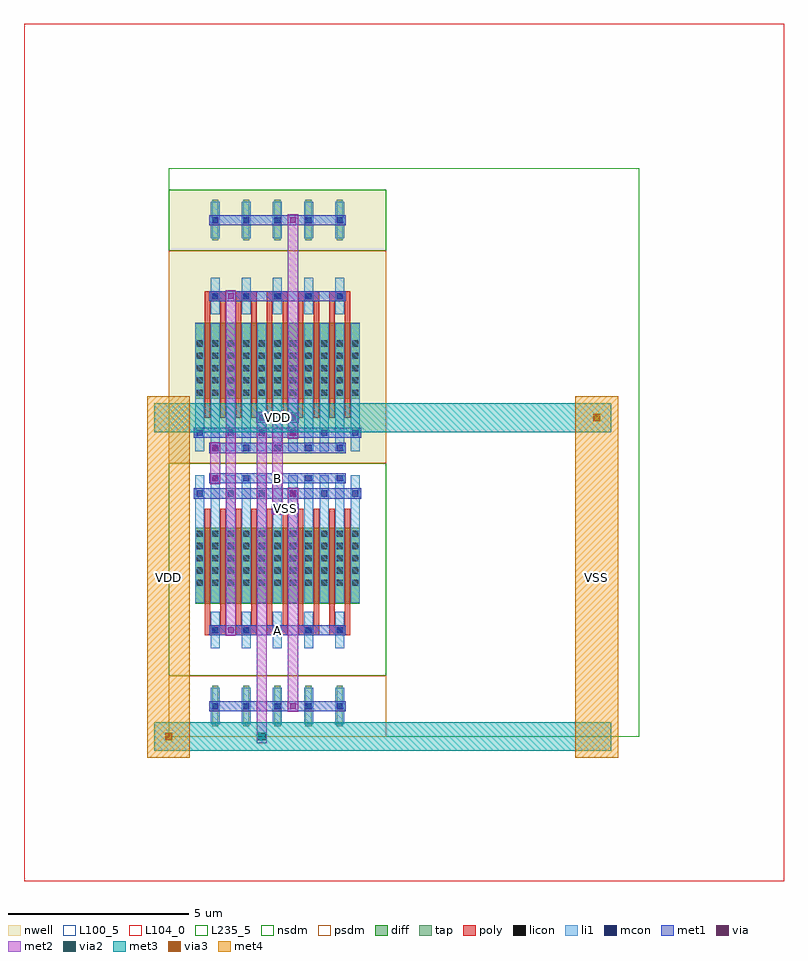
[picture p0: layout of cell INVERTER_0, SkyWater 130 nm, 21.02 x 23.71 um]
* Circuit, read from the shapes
.subckt INVERTER_0 A B VDD VSS
XM1 B A VSS VSS sky130_fd_pr__nfet_01v8 w=2.1 l=0.15 m=10
XM2 B A VDD VDD sky130_fd_pr__pfet_01v8 w=2.1 l=0.15 m=10
.ends

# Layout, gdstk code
import gdstk
lib = gdstk.Library(unit=1e-6, precision=1e-09)
def R(c, l, rs):  # rectangles x0, y0, x1, y1
    for r in rs: c.add(gdstk.rectangle(r[:2], r[2:], *l))
def A(c, l, x, y, w, h, nx, ny, dx, dy):  # array of equal rectangles
    R(c, l, [(x+i*dx, y+j*dy, x+i*dx+w, y+j*dy+h) for i in range(nx) for j in range(ny)])
def P(c, l, *ps):  # polygons
    for p in ps: c.add(gdstk.Polygon(p, *l))
nwell = (64, 20)
diff = (65, 20)
tap = (65, 44)
poly = (66, 20)
licon = (66, 44)
li1 = (67, 20)
mcon = (67, 44)
met1 = (68, 20)
via = (68, 44)
met2 = (69, 20)
via2 = (69, 44)
met3 = (70, 20)
via3 = (70, 44)
met4 = (71, 20)
nsdm = (93, 44)
psdm = (94, 20)
L100_5 = (100, 5)
L104_0 = (104, 0)
L235_5 = (235, 5)

nmos_s_97854001_x5_y1_16 = lib.new_cell('NMOS_S_97854001_X5_Y1_1676573813_1676573813')
R(nmos_s_97854001_x5_y1_16, diff, [(0.735,1.785,5.285,3.885)])
A(nmos_s_97854001_x5_y1_16, tap, 1.205, 6.16, 0.17, 1.12, 5, 1, 0.86, 0)
A(nmos_s_97854001_x5_y1_16, poly, 1, 1.26, 0.15, 3.36, 10, 1, 0.43, 0)
A(nmos_s_97854001_x5_y1_16, poly, 1, 4.485, 0.58, 0.27, 5, 1, 0.86, 0)
A(nmos_s_97854001_x5_y1_16, licon, 0.775, 1.865, 0.17, 0.17, 3, 5, 0.43, 0.34)
A(nmos_s_97854001_x5_y1_16, licon, 1.635, 1.865, 0.17, 0.17, 3, 5, 0.43, 0.34)
A(nmos_s_97854001_x5_y1_16, licon, 2.495, 1.865, 0.17, 0.17, 3, 5, 0.43, 0.34)
A(nmos_s_97854001_x5_y1_16, licon, 3.355, 1.865, 0.17, 0.17, 3, 5, 0.43, 0.34)
A(nmos_s_97854001_x5_y1_16, licon, 4.215, 1.865, 0.17, 0.17, 3, 5, 0.43, 0.34)
A(nmos_s_97854001_x5_y1_16, licon, 1.205, 4.535, 0.17, 0.17, 5, 2, 0.86, 2.1)
A(nmos_s_97854001_x5_y1_16, li1, 0.735, 0.335, 0.25, 3.53, 11, 1, 0.43, 0)
A(nmos_s_97854001_x5_y1_16, li1, 1.165, 4.115, 0.25, 1.01, 5, 2, 0.86, 2.1)
A(nmos_s_97854001_x5_y1_16, mcon, 1.205, 0.335, 0.17, 0.17, 5, 2, 0.86, 4.2)
A(nmos_s_97854001_x5_y1_16, mcon, 0.775, 0.755, 0.17, 0.17, 6, 1, 0.86, 0)
A(nmos_s_97854001_x5_y1_16, mcon, 1.205, 6.635, 0.17, 0.17, 5, 1, 0.86, 0)
R(nmos_s_97854001_x5_y1_16, met1, [(1.12,0.28,4.9,0.56), (0.69,0.7,5.33,0.98), (1.12,4.48,4.9,4.76), (1.12,6.58,4.9,6.86)])
R(nmos_s_97854001_x5_y1_16, via, [(3.365,0.765,3.515,0.915), (3.365,6.645,3.515,6.795)])
R(nmos_s_97854001_x5_y1_16, met2, [(3.3,0.68,3.58,6.88)])
R(nmos_s_97854001_x5_y1_16, nsdm, [(0,0,6.02,5.88)])
R(nmos_s_97854001_x5_y1_16, psdm, [(0,5.88,6.02,7.56)])
R(nmos_s_97854001_x5_y1_16, L100_5, [(0,0,6.02,7.56)])

pmos_s_86637345_x5_y1_16 = lib.new_cell('PMOS_S_86637345_X5_Y1_1676573814_1676573813')
R(pmos_s_86637345_x5_y1_16, nwell, [(0,0,6.02,7.56)])
R(pmos_s_86637345_x5_y1_16, diff, [(0.735,1.785,5.285,3.885)])
A(pmos_s_86637345_x5_y1_16, tap, 1.205, 6.16, 0.17, 1.12, 5, 1, 0.86, 0)
A(pmos_s_86637345_x5_y1_16, poly, 1, 1.26, 0.15, 3.36, 10, 1, 0.43, 0)
A(pmos_s_86637345_x5_y1_16, poly, 1, 4.485, 0.58, 0.27, 5, 1, 0.86, 0)
A(pmos_s_86637345_x5_y1_16, licon, 0.775, 1.865, 0.17, 0.17, 3, 5, 0.43, 0.34)
A(pmos_s_86637345_x5_y1_16, licon, 1.635, 1.865, 0.17, 0.17, 3, 5, 0.43, 0.34)
A(pmos_s_86637345_x5_y1_16, licon, 2.495, 1.865, 0.17, 0.17, 3, 5, 0.43, 0.34)
A(pmos_s_86637345_x5_y1_16, licon, 3.355, 1.865, 0.17, 0.17, 3, 5, 0.43, 0.34)
A(pmos_s_86637345_x5_y1_16, licon, 4.215, 1.865, 0.17, 0.17, 3, 5, 0.43, 0.34)
A(pmos_s_86637345_x5_y1_16, licon, 1.205, 4.535, 0.17, 0.17, 5, 2, 0.86, 2.1)
A(pmos_s_86637345_x5_y1_16, li1, 0.735, 0.335, 0.25, 3.53, 11, 1, 0.43, 0)
A(pmos_s_86637345_x5_y1_16, li1, 1.165, 4.115, 0.25, 1.01, 5, 2, 0.86, 2.1)
A(pmos_s_86637345_x5_y1_16, mcon, 1.205, 0.335, 0.17, 0.17, 5, 2, 0.86, 4.2)
A(pmos_s_86637345_x5_y1_16, mcon, 0.775, 0.755, 0.17, 0.17, 6, 1, 0.86, 0)
A(pmos_s_86637345_x5_y1_16, mcon, 1.205, 6.635, 0.17, 0.17, 5, 1, 0.86, 0)
R(pmos_s_86637345_x5_y1_16, met1, [(1.12,0.28,4.9,0.56), (0.69,0.7,5.33,0.98), (1.12,4.48,4.9,4.76), (1.12,6.58,4.9,6.86)])
R(pmos_s_86637345_x5_y1_16, via, [(3.365,0.765,3.515,0.915), (3.365,6.645,3.515,6.795)])
R(pmos_s_86637345_x5_y1_16, met2, [(3.3,0.68,3.58,6.88)])
R(pmos_s_86637345_x5_y1_16, nsdm, [(0,5.88,6.02,7.56)])
R(pmos_s_86637345_x5_y1_16, psdm, [(0,0,6.02,5.88)])
R(pmos_s_86637345_x5_y1_16, L100_5, [(0,0,6.02,7.56)])

inv_986780_pg0_0_0_16765 = lib.new_cell('INV_986780_PG0_0_0_1676573813')
R(inv_986780_pg0_0_0_16765, met1, [(1.56,2.8,1.88,3.08), (1.56,2.8,1.88,3.08), (1.13,7,1.45,7.28), (1.13,7,1.45,7.28), (1.13,7.84,1.45,8.12), (1.13,7.84,1.45,8.12), (1.56,12.04,1.88,12.32), (1.56,12.04,1.88,12.32)])
P(inv_986780_pg0_0_0_16765, met1, [(0,0),(0,0),(0,0),(0,0)],
  [(0,0),(0,0),(0,0),(0,0)],
  [(0,0),(0,0),(0,0),(0,0)],
  [(0,0),(0,0),(0,0),(0,0)])
R(inv_986780_pg0_0_0_16765, via, [(1.645,2.865,1.795,3.015), (1.645,2.865,1.795,3.015), (1.215,7.065,1.365,7.215), (1.215,7.065,1.365,7.215), (1.215,7.905,1.365,8.055), (1.215,7.905,1.365,8.055), (1.645,12.105,1.795,12.255), (1.645,12.105,1.795,12.255)])
R(inv_986780_pg0_0_0_16765, met2, [(1.58,2.78,1.86,3.1), (1.58,2.78,1.86,3.1), (1.58,2.94,1.86,12.18), (1.15,6.98,1.43,7.3), (1.15,6.98,1.43,7.3), (1.15,7.14,1.43,7.98), (1.15,7.82,1.43,8.14), (1.15,7.82,1.43,8.14), (1.58,12.02,1.86,12.34), (1.58,12.02,1.86,12.34)])
P(inv_986780_pg0_0_0_16765, met2, [(0,0),(0,0),(0,0),(0,0)],
  [(0,0),(0,0),(0,0),(0,0)])
R(inv_986780_pg0_0_0_16765, L235_5, [(0,0,6.02,15.12)])
inv_986780_pg0_0_0_16765.add(gdstk.Reference(nmos_s_97854001_x5_y1_16, (0,7.56), x_reflection=True))
inv_986780_pg0_0_0_16765.add(gdstk.Reference(pmos_s_86637345_x5_y1_16, (0,7.56)))

inverter_0 = lib.new_cell('INVERTER_0')
R(inverter_0, met1, [(2.85,6.16,3.17,6.44), (2.85,6.16,3.17,6.44), (3.01,6.16,3.44,6.44), (3.28,6.16,3.6,6.44), (3.28,6.16,3.6,6.44), (2.42,8.68,2.74,8.96), (2.42,8.68,2.74,8.96), (2.58,8.68,3.44,8.96), (3.28,8.68,3.6,8.96), (3.28,8.68,3.6,8.96)])
P(inverter_0, met1, [(0,0),(0,0),(0,0),(0,0)],
  [(0,0),(0,0),(0,0),(0,0)],
  [(0,0),(0,0),(0,0),(0,0)],
  [(0,0),(0,0),(0,0),(0,0)],
  [(0,0),(0,0),(0,0),(0,0)],
  [(0,0),(0,0),(0,0),(0,0)],
  [(0,0),(0,0),(0,0),(0,0)],
  [(0,0),(0,0),(0,0),(0,0)],
  [(0,0),(0,0),(0,0),(0,0)],
  [(0,0),(0,0),(0,0),(0,0)])
R(inverter_0, via, [(2.935,6.225,3.085,6.375), (2.935,6.225,3.085,6.375), (3.365,6.225,3.515,6.375), (3.365,6.225,3.515,6.375), (2.505,8.745,2.655,8.895), (2.505,8.745,2.655,8.895), (3.365,8.745,3.515,8.895), (3.365,8.745,3.515,8.895)])
R(inverter_0, met2, [(2.44,-0.185,2.72,0.185), (2.44,-0.185,2.72,0.185), (2.44,0,2.72,8.82), (2.87,6.14,3.15,6.46), (2.87,6.14,3.15,6.46), (3.3,6.14,3.58,6.46), (3.3,6.14,3.58,6.46), (2.87,6.3,3.15,8.82), (2.87,8.635,3.15,9.005), (2.87,8.635,3.15,9.005), (2.44,8.66,2.72,8.98), (2.44,8.66,2.72,8.98), (3.3,8.66,3.58,8.98), (3.3,8.66,3.58,8.98)])
P(inverter_0, met2, [(0,0),(0,0),(0,0),(0,0)],
  [(0,0),(0,0),(0,0),(0,0)])
R(inverter_0, via2, [(2.48,-0.1,2.68,0.1), (2.48,-0.1,2.68,0.1), (2.91,8.72,3.11,8.92), (2.91,8.72,3.11,8.92)])
A(inverter_0, met3, -0.4, -0.4, 4.24, 0.8, 3, 2, 3.44, 8.82)
R(inverter_0, met3, [(-0.165,-0.4,0.165,0.4), (2.415,-0.4,2.745,0.4), (2.415,-0.4,2.745,0.4), (9.92,-0.4,12.24,0.4), (2.845,8.42,3.175,9.22), (2.845,8.42,3.175,9.22), (9.92,8.42,12.24,9.22), (11.675,8.42,12.005,9.22)])
R(inverter_0, via3, [(-0.1,-0.1,0.1,0.1), (11.74,8.72,11.94,8.92)])
R(inverter_0, met4, [(-0.59,-0.59,0.59,9.41), (11.25,-0.59,12.43,9.41), (-0.59,-0.165,0.59,0.165), (11.25,8.655,12.43,8.985)])
R(inverter_0, L104_0, [(-4,-4,17.02,19.71)])
R(inverter_0, L235_5, [(0,0,13.02,15.71)])
inverter_0.add(gdstk.Reference(inv_986780_pg0_0_0_16765, (0,0)))
inverter_0.add(gdstk.Label('A', (3.01,2.94), layer=68, texttype=5))
inverter_0.add(gdstk.Label('B', (3.01,7.14), layer=68, texttype=5))
inverter_0.add(gdstk.Label('VSS', (11.84,4.41), layer=71, texttype=5))
inverter_0.add(gdstk.Label('VSS', (3.225,6.3), layer=68, texttype=5))
inverter_0.add(gdstk.Label('VSS', (11.84,4.41), layer=71, texttype=5))
inverter_0.add(gdstk.Label('VSS', (11.84,4.41), layer=71, texttype=5))
inverter_0.add(gdstk.Label('VSS', (11.84,4.41), layer=71, texttype=5))
inverter_0.add(gdstk.Label('VDD', (0,4.41), layer=71, texttype=5))
inverter_0.add(gdstk.Label('VDD', (3.01,8.82), layer=68, texttype=5))
inverter_0.add(gdstk.Label('VDD', (0,4.41), layer=71, texttype=5))
inverter_0.add(gdstk.Label('VDD', (0,4.41), layer=71, texttype=5))
inverter_0.add(gdstk.Label('VDD', (0,4.41), layer=71, texttype=5))

lib.write_gds('INVERTER_0.gds')
